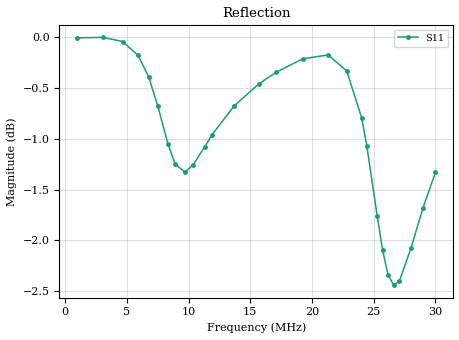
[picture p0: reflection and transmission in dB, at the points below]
! ListType=Log
# MHz S RI R 50
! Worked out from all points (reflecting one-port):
!   200 points, 1 MHz to 30 MHz, reference 50 ohm
!   lowest |S11| = -2.4 dB at 26.62 MHz (marker M1), VSWR 7.17, Z = 7.79 + j16.9 ohm
!   phase of S11 starts at -10 deg and turns -662 deg over the sweep
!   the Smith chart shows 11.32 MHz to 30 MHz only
!   S11 on the Smith chart (normalised r, x): 11.32 MHz: 0.15, +1.21; 17.07 MHz: 21, +25; 22.82 MHz: 0.06, -1.42; 25.29 MHz: 0.11, -0.22; 27.08 MHz: 0.18, +0.54; 30 MHz: 0.45, +2.16
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1  0.9853 -0.1678
3.08958  0.8509 -0.5253
4.656341  0.5808 -0.8083
5.915111  0.1599 -0.9667
6.781795  -0.2614 -0.9196
7.514169  -0.6325 -0.6749
8.325633  -0.8704 -0.1686
8.914729  -0.8306 0.2462
9.710056  -0.5412 0.6663
10.39711  -0.214 0.8389
11.32469  0.1774 0.8656
11.9205  0.372 0.8148
13.66709  0.7308 0.5669
15.6696  0.9126 0.2581
17.06756  0.9599 0.0458
19.2367  0.9292 -0.2984
21.31409  0.7187 -0.6667
22.82221  0.3267 -0.9054
24.02293  -0.21 -0.8883
24.43704  -0.4173 -0.78
25.28681  -0.7371 -0.3514
25.72271  -0.7829 -0.0625
26.16613  -0.7303 0.224
26.61719  -0.5939 0.4664
27.07603  -0.4062 0.6406
28.01756  -0.00173 0.7874
28.99184  0.3325 0.7543
30  0.572 0.6395
